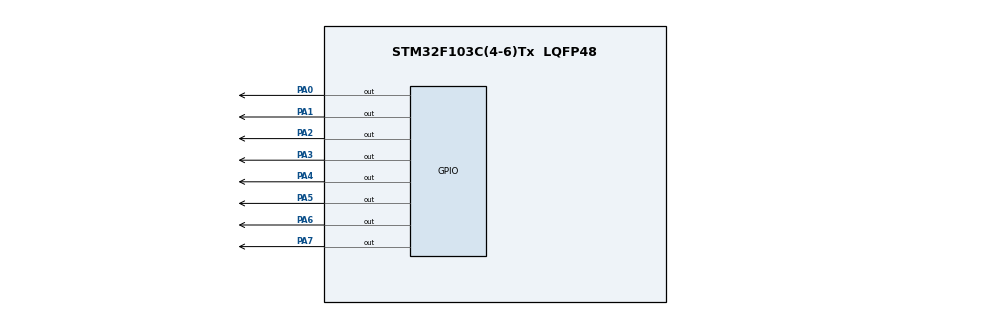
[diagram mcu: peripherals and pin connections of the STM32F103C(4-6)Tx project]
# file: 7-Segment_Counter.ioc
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Mcu.Family=STM32F1
ProjectManager.StackSize=0x400
PA0-WKUP.Signal=GPIO_Output
PA13.Signal=SYS_JTMS-SWDIO
ProjectManager.TargetToolchain=MDK-ARM V5.27
PA1.Signal=GPIO_Output
PA5.Signal=GPIO_Output
board=custom
RCC.APB2Freq_Value=8000000
PA14.Mode=Serial_Wire
PA13.Mode=Serial_Wire
Mcu.Name=STM32F103C(4-6)Tx
PA2.Signal=GPIO_Output
PA4.Signal=GPIO_Output
Mcu.Package=LQFP48
PA6.Signal=GPIO_Output
PA14.Signal=SYS_JTCK-SWCLK
ProjectManager.HeapSize=0x200
NVIC.PriorityGroup=NVIC_PRIORITYGROUP_4
RCC.APB1Freq_Value=8000000
PA3.Signal=GPIO_Output
PA7.Signal=GPIO_Output

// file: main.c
/* USER CODE BEGIN Header */
/**
  ******************************************************************************
  * @file           : main.c
  * @brief          : Main program body
  ******************************************************************************
  * @attention
  *
  * <h2><center>&copy; Copyright (c) 2025 STMicroelectronics.
  * All rights reserved.</center></h2>
  *
  * This software component is licensed by ST under BSD 3-Clause license,
  * the "License"; You may not use this file except in compliance with the
  * License. You may obtain a copy of the License at:
  *                        opensource.org/licenses/BSD-3-Clause
  *
  ******************************************************************************
  */
/* USER CODE END Header */

#include "main.h"

/* USER CODE BEGIN PV */
unsigned char number[10]={0x3F,0x06,0x5B,0x4F,0x66,0x6D,0x7D,0x07,0x7F,0x6F};

int d = 0;
int y = 0;

/* USER CODE END PV */

void SystemClock_Config(void);
static void MX_GPIO_Init(void);

int main(void)
{

  /* MCU Configuration--------------------------------------------------------*/

  /* Reset of all peripherals, Initializes the Flash interface and the Systick. */
  HAL_Init();

  /* Configure the system clock */
  SystemClock_Config();

  /* Initialize all configured peripherals */
  MX_GPIO_Init();
  /* USER CODE BEGIN 2 */
HAL_GPIO_WritePin(GPIOB,GPIO_PIN_0,GPIO_PIN_SET); //OFF page 1
HAL_GPIO_WritePin(GPIOB,GPIO_PIN_1,GPIO_PIN_SET); //OFF page 2
  /* USER CODE END 2 */

  /* Infinite loop */
  while (1)
  {

    /* USER CODE BEGIN 3 */

    HAL_GPIO_WritePin(GPIOA, 0xFF, GPIO_PIN_RESET);
    HAL_GPIO_WritePin(GPIOB, GPIO_PIN_1, GPIO_PIN_RESET); // ON page 2 (PB1)
    HAL_GPIO_WritePin(GPIOA, number[y], GPIO_PIN_SET);
    HAL_Delay(30);
    HAL_GPIO_WritePin(GPIOB, GPIO_PIN_1, GPIO_PIN_SET); // OFF page 2 (PB1)

    HAL_GPIO_WritePin(GPIOA, 0xFF, GPIO_PIN_RESET);
    HAL_GPIO_WritePin(GPIOB, GPIO_PIN_0, GPIO_PIN_RESET); // ON page 1 (PB0)
    HAL_GPIO_WritePin(GPIOA, number[d], GPIO_PIN_SET);
    HAL_Delay(30);
    HAL_GPIO_WritePin(GPIOB, GPIO_PIN_0, GPIO_PIN_SET); // OFF page 1 (PB0)

    y++;
		if(y == 10){
			y = 0;
			d++;
				if(d == 10)
						d = 0;
}

}

  }
  /* USER CODE END 3 */

void SystemClock_Config(void)
{
  RCC_OscInitTypeDef RCC_OscInitStruct = {0};
  RCC_ClkInitTypeDef RCC_ClkInitStruct = {0};

  /** Initializes the CPU, AHB and APB busses clocks
  */
  RCC_OscInitStruct.OscillatorType = RCC_OSCILLATORTYPE_HSI;
  RCC_OscInitStruct.HSIState = RCC_HSI_ON;
  RCC_OscInitStruct.HSICalibrationValue = RCC_HSICALIBRATION_DEFAULT;
  RCC_OscInitStruct.PLL.PLLState = RCC_PLL_NONE;
  if (HAL_RCC_OscConfig(&RCC_OscInitStruct) != HAL_OK)
  {
    Error_Handler();
  }
  /** Initializes the CPU, AHB and APB busses clocks
  */
  RCC_ClkInitStruct.ClockType = RCC_CLOCKTYPE_HCLK|RCC_CLOCKTYPE_SYSCLK
                              |RCC_CLOCKTYPE_PCLK1|RCC_CLOCKTYPE_PCLK2;
  RCC_ClkInitStruct.SYSCLKSource = RCC_SYSCLKSOURCE_HSI;
  RCC_ClkInitStruct.AHBCLKDivider = RCC_SYSCLK_DIV1;
  RCC_ClkInitStruct.APB1CLKDivider = RCC_HCLK_DIV1;
  RCC_ClkInitStruct.APB2CLKDivider = RCC_HCLK_DIV1;

  if (HAL_RCC_ClockConfig(&RCC_ClkInitStruct, FLASH_LATENCY_0) != HAL_OK)
  {
    Error_Handler();
  }
}

static void MX_GPIO_Init(void)
{
  GPIO_InitTypeDef GPIO_InitStruct = {0};

  /* GPIO Ports Clock Enable */
  __HAL_RCC_GPIOA_CLK_ENABLE();
  __HAL_RCC_GPIOB_CLK_ENABLE();

  /*Configure GPIO pin Output Level */
  HAL_GPIO_WritePin(GPIOA, GPIO_PIN_0|GPIO_PIN_1|GPIO_PIN_2|GPIO_PIN_3
                          |GPIO_PIN_4|GPIO_PIN_5|GPIO_PIN_6|GPIO_PIN_7, GPIO_PIN_RESET);

  /*Configure GPIO pin Output Level */
  HAL_GPIO_WritePin(GPIOB, GPIO_PIN_0|GPIO_PIN_1, GPIO_PIN_RESET);

  /*Configure GPIO pins : PA0 PA1 PA2 PA3
                           PA4 PA5 PA6 PA7 */
  GPIO_InitStruct.Pin = GPIO_PIN_0|GPIO_PIN_1|GPIO_PIN_2|GPIO_PIN_3
                          |GPIO_PIN_4|GPIO_PIN_5|GPIO_PIN_6|GPIO_PIN_7;
  GPIO_InitStruct.Mode = GPIO_MODE_OUTPUT_PP;
  GPIO_InitStruct.Pull = GPIO_NOPULL;
  GPIO_InitStruct.Speed = GPIO_SPEED_FREQ_LOW;
  HAL_GPIO_Init(GPIOA, &GPIO_InitStruct);

  /*Configure GPIO pins : PB0 PB1 */
  GPIO_InitStruct.Pin = GPIO_PIN_0|GPIO_PIN_1;
  GPIO_InitStruct.Mode = GPIO_MODE_OUTPUT_PP;
  GPIO_InitStruct.Pull = GPIO_NOPULL;
  GPIO_InitStruct.Speed = GPIO_SPEED_FREQ_LOW;
  HAL_GPIO_Init(GPIOB, &GPIO_InitStruct);

}

void Error_Handler(void)
{
}

/************************ (C) COPYRIGHT STMicroelectronics *****END OF FILE****/
